VERSION 5.7 ;
  NOWIREEXTENSIONATPIN ON ;
  DIVIDERCHAR "/" ;
  BUSBITCHARS "[]" ;
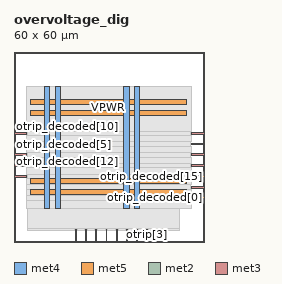
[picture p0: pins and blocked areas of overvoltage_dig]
MACRO overvoltage_dig
  CLASS BLOCK ;
  FOREIGN overvoltage_dig ;
  ORIGIN 0.000 0.000 ;
  SIZE 60.000 BY 60.000 ;
  PIN VGND
    DIRECTION INOUT ;
    USE GROUND ;
    PORT
      LAYER met4 ;
        RECT 13.020 10.640 14.620 49.200 ;
    END
    PORT
      LAYER met4 ;
        RECT 38.020 10.640 39.620 49.200 ;
    END
    PORT
      LAYER met5 ;
        RECT 5.280 18.380 54.520 19.980 ;
    END
    PORT
      LAYER met5 ;
        RECT 5.280 43.380 54.520 44.980 ;
    END
  END VGND
  PIN VPWR
    DIRECTION INOUT ;
    USE POWER ;
    PORT
      LAYER met4 ;
        RECT 9.720 10.640 11.320 49.200 ;
    END
    PORT
      LAYER met4 ;
        RECT 34.720 10.640 36.320 49.200 ;
    END
    PORT
      LAYER met5 ;
        RECT 5.280 15.080 54.520 16.680 ;
    END
    PORT
      LAYER met5 ;
        RECT 5.280 40.080 54.520 41.680 ;
    END
  END VPWR
  PIN otrip[0]
    DIRECTION INPUT ;
    USE SIGNAL ;
    ANTENNAGATEAREA 0.196500 ;
    PORT
      LAYER met2 ;
        RECT 32.290 0.000 32.570 4.000 ;
    END
  END otrip[0]
  PIN otrip[1]
    DIRECTION INPUT ;
    USE SIGNAL ;
    ANTENNAGATEAREA 0.196500 ;
    PORT
      LAYER met2 ;
        RECT 35.510 0.000 35.790 4.000 ;
    END
  END otrip[1]
  PIN otrip[2]
    DIRECTION INPUT ;
    USE SIGNAL ;
    ANTENNAGATEAREA 0.196500 ;
    PORT
      LAYER met2 ;
        RECT 38.730 0.000 39.010 4.000 ;
    END
  END otrip[2]
  PIN otrip[3]
    DIRECTION INPUT ;
    USE SIGNAL ;
    ANTENNAGATEAREA 0.196500 ;
    PORT
      LAYER met2 ;
        RECT 41.950 0.000 42.230 4.000 ;
    END
  END otrip[3]
  PIN otrip_decoded[0]
    DIRECTION OUTPUT ;
    USE SIGNAL ;
    ANTENNADIFFAREA 0.445500 ;
    PORT
      LAYER met3 ;
        RECT 56.000 13.640 60.000 14.240 ;
    END
  END otrip_decoded[0]
  PIN otrip_decoded[10]
    DIRECTION OUTPUT ;
    USE SIGNAL ;
    ANTENNADIFFAREA 0.445500 ;
    PORT
      LAYER met3 ;
        RECT 0.000 34.040 4.000 34.640 ;
    END
  END otrip_decoded[10]
  PIN otrip_decoded[11]
    DIRECTION OUTPUT ;
    USE SIGNAL ;
    ANTENNADIFFAREA 0.445500 ;
    PORT
      LAYER met3 ;
        RECT 56.000 17.040 60.000 17.640 ;
    END
  END otrip_decoded[11]
  PIN otrip_decoded[12]
    DIRECTION OUTPUT ;
    USE SIGNAL ;
    ANTENNADIFFAREA 0.445500 ;
    PORT
      LAYER met3 ;
        RECT 0.000 27.240 4.000 27.840 ;
    END
  END otrip_decoded[12]
  PIN otrip_decoded[13]
    DIRECTION OUTPUT ;
    USE SIGNAL ;
    ANTENNADIFFAREA 0.445500 ;
    PORT
      LAYER met3 ;
        RECT 56.000 23.840 60.000 24.440 ;
    END
  END otrip_decoded[13]
  PIN otrip_decoded[14]
    DIRECTION OUTPUT ;
    USE SIGNAL ;
    ANTENNADIFFAREA 0.445500 ;
    PORT
      LAYER met3 ;
        RECT 56.000 34.040 60.000 34.640 ;
    END
  END otrip_decoded[14]
  PIN otrip_decoded[15]
    DIRECTION OUTPUT ;
    USE SIGNAL ;
    ANTENNADIFFAREA 0.445500 ;
    PORT
      LAYER met3 ;
        RECT 56.000 20.440 60.000 21.040 ;
    END
  END otrip_decoded[15]
  PIN otrip_decoded[1]
    DIRECTION OUTPUT ;
    USE SIGNAL ;
    ANTENNADIFFAREA 0.445500 ;
    PORT
      LAYER met2 ;
        RECT 25.850 0.000 26.130 4.000 ;
    END
  END otrip_decoded[1]
  PIN otrip_decoded[2]
    DIRECTION OUTPUT ;
    USE SIGNAL ;
    ANTENNADIFFAREA 0.445500 ;
    PORT
      LAYER met2 ;
        RECT 19.410 0.000 19.690 4.000 ;
    END
  END otrip_decoded[2]
  PIN otrip_decoded[3]
    DIRECTION OUTPUT ;
    USE SIGNAL ;
    ANTENNADIFFAREA 0.445500 ;
    PORT
      LAYER met3 ;
        RECT 0.000 20.440 4.000 21.040 ;
    END
  END otrip_decoded[3]
  PIN otrip_decoded[4]
    DIRECTION OUTPUT ;
    USE SIGNAL ;
    ANTENNADIFFAREA 0.445500 ;
    PORT
      LAYER met2 ;
        RECT 22.630 0.000 22.910 4.000 ;
    END
  END otrip_decoded[4]
  PIN otrip_decoded[5]
    DIRECTION OUTPUT ;
    USE SIGNAL ;
    ANTENNADIFFAREA 0.445500 ;
    PORT
      LAYER met3 ;
        RECT 0.000 30.640 4.000 31.240 ;
    END
  END otrip_decoded[5]
  PIN otrip_decoded[6]
    DIRECTION OUTPUT ;
    USE SIGNAL ;
    ANTENNADIFFAREA 0.445500 ;
    PORT
      LAYER met3 ;
        RECT 0.000 23.840 4.000 24.440 ;
    END
  END otrip_decoded[6]
  PIN otrip_decoded[7]
    DIRECTION OUTPUT ;
    USE SIGNAL ;
    ANTENNADIFFAREA 0.445500 ;
    PORT
      LAYER met3 ;
        RECT 56.000 30.640 60.000 31.240 ;
    END
  END otrip_decoded[7]
  PIN otrip_decoded[8]
    DIRECTION OUTPUT ;
    USE SIGNAL ;
    ANTENNADIFFAREA 0.445500 ;
    PORT
      LAYER met3 ;
        RECT 56.000 27.240 60.000 27.840 ;
    END
  END otrip_decoded[8]
  PIN otrip_decoded[9]
    DIRECTION OUTPUT ;
    USE SIGNAL ;
    ANTENNADIFFAREA 0.445500 ;
    PORT
      LAYER met2 ;
        RECT 29.070 0.000 29.350 4.000 ;
    END
  END otrip_decoded[9]
  OBS
      LAYER li1 ;
        RECT 5.520 10.795 54.280 49.045 ;
      LAYER met1 ;
        RECT 4.210 10.640 54.280 49.200 ;
      LAYER met2 ;
        RECT 4.230 4.280 52.350 49.145 ;
        RECT 4.230 3.670 19.130 4.280 ;
        RECT 19.970 3.670 22.350 4.280 ;
        RECT 23.190 3.670 25.570 4.280 ;
        RECT 26.410 3.670 28.790 4.280 ;
        RECT 29.630 3.670 32.010 4.280 ;
        RECT 32.850 3.670 35.230 4.280 ;
        RECT 36.070 3.670 38.450 4.280 ;
        RECT 39.290 3.670 41.670 4.280 ;
        RECT 42.510 3.670 52.350 4.280 ;
      LAYER met3 ;
        RECT 3.990 35.040 56.000 49.125 ;
        RECT 4.400 33.640 55.600 35.040 ;
        RECT 3.990 31.640 56.000 33.640 ;
        RECT 4.400 30.240 55.600 31.640 ;
        RECT 3.990 28.240 56.000 30.240 ;
        RECT 4.400 26.840 55.600 28.240 ;
        RECT 3.990 24.840 56.000 26.840 ;
        RECT 4.400 23.440 55.600 24.840 ;
        RECT 3.990 21.440 56.000 23.440 ;
        RECT 4.400 20.040 55.600 21.440 ;
        RECT 3.990 18.040 56.000 20.040 ;
        RECT 3.990 16.640 55.600 18.040 ;
        RECT 3.990 14.640 56.000 16.640 ;
        RECT 3.990 13.240 55.600 14.640 ;
        RECT 3.990 10.715 56.000 13.240 ;
  END
END overvoltage_dig
END LIBRARY

